# Generated by FakeRAM 2.0
VERSION 5.7 ;
BUSBITCHARS "[]" ;
PROPERTYDEFINITIONS
  MACRO width INTEGER ;
  MACRO depth INTEGER ;
  MACRO banks INTEGER ;
END PROPERTYDEFINITIONS
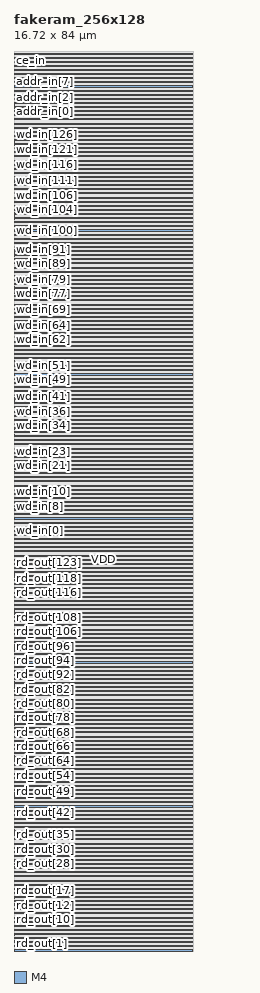
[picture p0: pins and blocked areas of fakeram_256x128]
MACRO fakeram_256x128
  PROPERTY width 128 ;
  PROPERTY depth 256 ;
  PROPERTY banks 1 ;
  FOREIGN fakeram_256x128 0 0 ;
  SYMMETRY X Y R90 ;
  SIZE 16.720 BY 84.000 ;
  CLASS BLOCK ;
  PIN rd_out[0]
    DIRECTION OUTPUT ;
    USE SIGNAL ;
    SHAPE ABUTMENT ;
    PORT
      LAYER M4 ;
      RECT 0.000 0.048 0.024 0.072 ;
    END
  END rd_out[0]
  PIN rd_out[1]
    DIRECTION OUTPUT ;
    USE SIGNAL ;
    SHAPE ABUTMENT ;
    PORT
      LAYER M4 ;
      RECT 0.000 0.336 0.024 0.360 ;
    END
  END rd_out[1]
  PIN rd_out[2]
    DIRECTION OUTPUT ;
    USE SIGNAL ;
    SHAPE ABUTMENT ;
    PORT
      LAYER M4 ;
      RECT 0.000 0.624 0.024 0.648 ;
    END
  END rd_out[2]
  PIN rd_out[3]
    DIRECTION OUTPUT ;
    USE SIGNAL ;
    SHAPE ABUTMENT ;
    PORT
      LAYER M4 ;
      RECT 0.000 0.912 0.024 0.936 ;
    END
  END rd_out[3]
  PIN rd_out[4]
    DIRECTION OUTPUT ;
    USE SIGNAL ;
    SHAPE ABUTMENT ;
    PORT
      LAYER M4 ;
      RECT 0.000 1.200 0.024 1.224 ;
    END
  END rd_out[4]
  PIN rd_out[5]
    DIRECTION OUTPUT ;
    USE SIGNAL ;
    SHAPE ABUTMENT ;
    PORT
      LAYER M4 ;
      RECT 0.000 1.488 0.024 1.512 ;
    END
  END rd_out[5]
  PIN rd_out[6]
    DIRECTION OUTPUT ;
    USE SIGNAL ;
    SHAPE ABUTMENT ;
    PORT
      LAYER M4 ;
      RECT 0.000 1.776 0.024 1.800 ;
    END
  END rd_out[6]
  PIN rd_out[7]
    DIRECTION OUTPUT ;
    USE SIGNAL ;
    SHAPE ABUTMENT ;
    PORT
      LAYER M4 ;
      RECT 0.000 2.064 0.024 2.088 ;
    END
  END rd_out[7]
  PIN rd_out[8]
    DIRECTION OUTPUT ;
    USE SIGNAL ;
    SHAPE ABUTMENT ;
    PORT
      LAYER M4 ;
      RECT 0.000 2.352 0.024 2.376 ;
    END
  END rd_out[8]
  PIN rd_out[9]
    DIRECTION OUTPUT ;
    USE SIGNAL ;
    SHAPE ABUTMENT ;
    PORT
      LAYER M4 ;
      RECT 0.000 2.640 0.024 2.664 ;
    END
  END rd_out[9]
  PIN rd_out[10]
    DIRECTION OUTPUT ;
    USE SIGNAL ;
    SHAPE ABUTMENT ;
    PORT
      LAYER M4 ;
      RECT 0.000 2.928 0.024 2.952 ;
    END
  END rd_out[10]
  PIN rd_out[11]
    DIRECTION OUTPUT ;
    USE SIGNAL ;
    SHAPE ABUTMENT ;
    PORT
      LAYER M4 ;
      RECT 0.000 3.216 0.024 3.240 ;
    END
  END rd_out[11]
  PIN rd_out[12]
    DIRECTION OUTPUT ;
    USE SIGNAL ;
    SHAPE ABUTMENT ;
    PORT
      LAYER M4 ;
      RECT 0.000 3.504 0.024 3.528 ;
    END
  END rd_out[12]
  PIN rd_out[13]
    DIRECTION OUTPUT ;
    USE SIGNAL ;
    SHAPE ABUTMENT ;
    PORT
      LAYER M4 ;
      RECT 0.000 3.792 0.024 3.816 ;
    END
  END rd_out[13]
  PIN rd_out[14]
    DIRECTION OUTPUT ;
    USE SIGNAL ;
    SHAPE ABUTMENT ;
    PORT
      LAYER M4 ;
      RECT 0.000 4.080 0.024 4.104 ;
    END
  END rd_out[14]
  PIN rd_out[15]
    DIRECTION OUTPUT ;
    USE SIGNAL ;
    SHAPE ABUTMENT ;
    PORT
      LAYER M4 ;
      RECT 0.000 4.368 0.024 4.392 ;
    END
  END rd_out[15]
  PIN rd_out[16]
    DIRECTION OUTPUT ;
    USE SIGNAL ;
    SHAPE ABUTMENT ;
    PORT
      LAYER M4 ;
      RECT 0.000 4.656 0.024 4.680 ;
    END
  END rd_out[16]
  PIN rd_out[17]
    DIRECTION OUTPUT ;
    USE SIGNAL ;
    SHAPE ABUTMENT ;
    PORT
      LAYER M4 ;
      RECT 0.000 4.944 0.024 4.968 ;
    END
  END rd_out[17]
  PIN rd_out[18]
    DIRECTION OUTPUT ;
    USE SIGNAL ;
    SHAPE ABUTMENT ;
    PORT
      LAYER M4 ;
      RECT 0.000 5.232 0.024 5.256 ;
    END
  END rd_out[18]
  PIN rd_out[19]
    DIRECTION OUTPUT ;
    USE SIGNAL ;
    SHAPE ABUTMENT ;
    PORT
      LAYER M4 ;
      RECT 0.000 5.520 0.024 5.544 ;
    END
  END rd_out[19]
  PIN rd_out[20]
    DIRECTION OUTPUT ;
    USE SIGNAL ;
    SHAPE ABUTMENT ;
    PORT
      LAYER M4 ;
      RECT 0.000 5.808 0.024 5.832 ;
    END
  END rd_out[20]
  PIN rd_out[21]
    DIRECTION OUTPUT ;
    USE SIGNAL ;
    SHAPE ABUTMENT ;
    PORT
      LAYER M4 ;
      RECT 0.000 6.096 0.024 6.120 ;
    END
  END rd_out[21]
  PIN rd_out[22]
    DIRECTION OUTPUT ;
    USE SIGNAL ;
    SHAPE ABUTMENT ;
    PORT
      LAYER M4 ;
      RECT 0.000 6.384 0.024 6.408 ;
    END
  END rd_out[22]
  PIN rd_out[23]
    DIRECTION OUTPUT ;
    USE SIGNAL ;
    SHAPE ABUTMENT ;
    PORT
      LAYER M4 ;
      RECT 0.000 6.672 0.024 6.696 ;
    END
  END rd_out[23]
  PIN rd_out[24]
    DIRECTION OUTPUT ;
    USE SIGNAL ;
    SHAPE ABUTMENT ;
    PORT
      LAYER M4 ;
      RECT 0.000 6.960 0.024 6.984 ;
    END
  END rd_out[24]
  PIN rd_out[25]
    DIRECTION OUTPUT ;
    USE SIGNAL ;
    SHAPE ABUTMENT ;
    PORT
      LAYER M4 ;
      RECT 0.000 7.248 0.024 7.272 ;
    END
  END rd_out[25]
  PIN rd_out[26]
    DIRECTION OUTPUT ;
    USE SIGNAL ;
    SHAPE ABUTMENT ;
    PORT
      LAYER M4 ;
      RECT 0.000 7.536 0.024 7.560 ;
    END
  END rd_out[26]
  PIN rd_out[27]
    DIRECTION OUTPUT ;
    USE SIGNAL ;
    SHAPE ABUTMENT ;
    PORT
      LAYER M4 ;
      RECT 0.000 7.824 0.024 7.848 ;
    END
  END rd_out[27]
  PIN rd_out[28]
    DIRECTION OUTPUT ;
    USE SIGNAL ;
    SHAPE ABUTMENT ;
    PORT
      LAYER M4 ;
      RECT 0.000 8.112 0.024 8.136 ;
    END
  END rd_out[28]
  PIN rd_out[29]
    DIRECTION OUTPUT ;
    USE SIGNAL ;
    SHAPE ABUTMENT ;
    PORT
      LAYER M4 ;
      RECT 0.000 8.400 0.024 8.424 ;
    END
  END rd_out[29]
  PIN rd_out[30]
    DIRECTION OUTPUT ;
    USE SIGNAL ;
    SHAPE ABUTMENT ;
    PORT
      LAYER M4 ;
      RECT 0.000 8.688 0.024 8.712 ;
    END
  END rd_out[30]
  PIN rd_out[31]
    DIRECTION OUTPUT ;
    USE SIGNAL ;
    SHAPE ABUTMENT ;
    PORT
      LAYER M4 ;
      RECT 0.000 8.976 0.024 9.000 ;
    END
  END rd_out[31]
  PIN rd_out[32]
    DIRECTION OUTPUT ;
    USE SIGNAL ;
    SHAPE ABUTMENT ;
    PORT
      LAYER M4 ;
      RECT 0.000 9.264 0.024 9.288 ;
    END
  END rd_out[32]
  PIN rd_out[33]
    DIRECTION OUTPUT ;
    USE SIGNAL ;
    SHAPE ABUTMENT ;
    PORT
      LAYER M4 ;
      RECT 0.000 9.552 0.024 9.576 ;
    END
  END rd_out[33]
  PIN rd_out[34]
    DIRECTION OUTPUT ;
    USE SIGNAL ;
    SHAPE ABUTMENT ;
    PORT
      LAYER M4 ;
      RECT 0.000 9.840 0.024 9.864 ;
    END
  END rd_out[34]
  PIN rd_out[35]
    DIRECTION OUTPUT ;
    USE SIGNAL ;
    SHAPE ABUTMENT ;
    PORT
      LAYER M4 ;
      RECT 0.000 10.128 0.024 10.152 ;
    END
  END rd_out[35]
  PIN rd_out[36]
    DIRECTION OUTPUT ;
    USE SIGNAL ;
    SHAPE ABUTMENT ;
    PORT
      LAYER M4 ;
      RECT 0.000 10.416 0.024 10.440 ;
    END
  END rd_out[36]
  PIN rd_out[37]
    DIRECTION OUTPUT ;
    USE SIGNAL ;
    SHAPE ABUTMENT ;
    PORT
      LAYER M4 ;
      RECT 0.000 10.704 0.024 10.728 ;
    END
  END rd_out[37]
  PIN rd_out[38]
    DIRECTION OUTPUT ;
    USE SIGNAL ;
    SHAPE ABUTMENT ;
    PORT
      LAYER M4 ;
      RECT 0.000 10.992 0.024 11.016 ;
    END
  END rd_out[38]
  PIN rd_out[39]
    DIRECTION OUTPUT ;
    USE SIGNAL ;
    SHAPE ABUTMENT ;
    PORT
      LAYER M4 ;
      RECT 0.000 11.280 0.024 11.304 ;
    END
  END rd_out[39]
  PIN rd_out[40]
    DIRECTION OUTPUT ;
    USE SIGNAL ;
    SHAPE ABUTMENT ;
    PORT
      LAYER M4 ;
      RECT 0.000 11.568 0.024 11.592 ;
    END
  END rd_out[40]
  PIN rd_out[41]
    DIRECTION OUTPUT ;
    USE SIGNAL ;
    SHAPE ABUTMENT ;
    PORT
      LAYER M4 ;
      RECT 0.000 11.856 0.024 11.880 ;
    END
  END rd_out[41]
  PIN rd_out[42]
    DIRECTION OUTPUT ;
    USE SIGNAL ;
    SHAPE ABUTMENT ;
    PORT
      LAYER M4 ;
      RECT 0.000 12.144 0.024 12.168 ;
    END
  END rd_out[42]
  PIN rd_out[43]
    DIRECTION OUTPUT ;
    USE SIGNAL ;
    SHAPE ABUTMENT ;
    PORT
      LAYER M4 ;
      RECT 0.000 12.432 0.024 12.456 ;
    END
  END rd_out[43]
  PIN rd_out[44]
    DIRECTION OUTPUT ;
    USE SIGNAL ;
    SHAPE ABUTMENT ;
    PORT
      LAYER M4 ;
      RECT 0.000 12.720 0.024 12.744 ;
    END
  END rd_out[44]
  PIN rd_out[45]
    DIRECTION OUTPUT ;
    USE SIGNAL ;
    SHAPE ABUTMENT ;
    PORT
      LAYER M4 ;
      RECT 0.000 13.008 0.024 13.032 ;
    END
  END rd_out[45]
  PIN rd_out[46]
    DIRECTION OUTPUT ;
    USE SIGNAL ;
    SHAPE ABUTMENT ;
    PORT
      LAYER M4 ;
      RECT 0.000 13.296 0.024 13.320 ;
    END
  END rd_out[46]
  PIN rd_out[47]
    DIRECTION OUTPUT ;
    USE SIGNAL ;
    SHAPE ABUTMENT ;
    PORT
      LAYER M4 ;
      RECT 0.000 13.584 0.024 13.608 ;
    END
  END rd_out[47]
  PIN rd_out[48]
    DIRECTION OUTPUT ;
    USE SIGNAL ;
    SHAPE ABUTMENT ;
    PORT
      LAYER M4 ;
      RECT 0.000 13.872 0.024 13.896 ;
    END
  END rd_out[48]
  PIN rd_out[49]
    DIRECTION OUTPUT ;
    USE SIGNAL ;
    SHAPE ABUTMENT ;
    PORT
      LAYER M4 ;
      RECT 0.000 14.160 0.024 14.184 ;
    END
  END rd_out[49]
  PIN rd_out[50]
    DIRECTION OUTPUT ;
    USE SIGNAL ;
    SHAPE ABUTMENT ;
    PORT
      LAYER M4 ;
      RECT 0.000 14.448 0.024 14.472 ;
    END
  END rd_out[50]
  PIN rd_out[51]
    DIRECTION OUTPUT ;
    USE SIGNAL ;
    SHAPE ABUTMENT ;
    PORT
      LAYER M4 ;
      RECT 0.000 14.736 0.024 14.760 ;
    END
  END rd_out[51]
  PIN rd_out[52]
    DIRECTION OUTPUT ;
    USE SIGNAL ;
    SHAPE ABUTMENT ;
    PORT
      LAYER M4 ;
      RECT 0.000 15.024 0.024 15.048 ;
    END
  END rd_out[52]
  PIN rd_out[53]
    DIRECTION OUTPUT ;
    USE SIGNAL ;
    SHAPE ABUTMENT ;
    PORT
      LAYER M4 ;
      RECT 0.000 15.312 0.024 15.336 ;
    END
  END rd_out[53]
  PIN rd_out[54]
    DIRECTION OUTPUT ;
    USE SIGNAL ;
    SHAPE ABUTMENT ;
    PORT
      LAYER M4 ;
      RECT 0.000 15.600 0.024 15.624 ;
    END
  END rd_out[54]
  PIN rd_out[55]
    DIRECTION OUTPUT ;
    USE SIGNAL ;
    SHAPE ABUTMENT ;
    PORT
      LAYER M4 ;
      RECT 0.000 15.888 0.024 15.912 ;
    END
  END rd_out[55]
  PIN rd_out[56]
    DIRECTION OUTPUT ;
    USE SIGNAL ;
    SHAPE ABUTMENT ;
    PORT
      LAYER M4 ;
      RECT 0.000 16.176 0.024 16.200 ;
    END
  END rd_out[56]
  PIN rd_out[57]
    DIRECTION OUTPUT ;
    USE SIGNAL ;
    SHAPE ABUTMENT ;
    PORT
      LAYER M4 ;
      RECT 0.000 16.464 0.024 16.488 ;
    END
  END rd_out[57]
  PIN rd_out[58]
    DIRECTION OUTPUT ;
    USE SIGNAL ;
    SHAPE ABUTMENT ;
    PORT
      LAYER M4 ;
      RECT 0.000 16.752 0.024 16.776 ;
    END
  END rd_out[58]
  PIN rd_out[59]
    DIRECTION OUTPUT ;
    USE SIGNAL ;
    SHAPE ABUTMENT ;
    PORT
      LAYER M4 ;
      RECT 0.000 17.040 0.024 17.064 ;
    END
  END rd_out[59]
  PIN rd_out[60]
    DIRECTION OUTPUT ;
    USE SIGNAL ;
    SHAPE ABUTMENT ;
    PORT
      LAYER M4 ;
      RECT 0.000 17.328 0.024 17.352 ;
    END
  END rd_out[60]
  PIN rd_out[61]
    DIRECTION OUTPUT ;
    USE SIGNAL ;
    SHAPE ABUTMENT ;
    PORT
      LAYER M4 ;
      RECT 0.000 17.616 0.024 17.640 ;
    END
  END rd_out[61]
  PIN rd_out[62]
    DIRECTION OUTPUT ;
    USE SIGNAL ;
    SHAPE ABUTMENT ;
    PORT
      LAYER M4 ;
      RECT 0.000 17.904 0.024 17.928 ;
    END
  END rd_out[62]
  PIN rd_out[63]
    DIRECTION OUTPUT ;
    USE SIGNAL ;
    SHAPE ABUTMENT ;
    PORT
      LAYER M4 ;
      RECT 0.000 18.192 0.024 18.216 ;
    END
  END rd_out[63]
  PIN rd_out[64]
    DIRECTION OUTPUT ;
    USE SIGNAL ;
    SHAPE ABUTMENT ;
    PORT
      LAYER M4 ;
      RECT 0.000 18.480 0.024 18.504 ;
    END
  END rd_out[64]
  PIN rd_out[65]
    DIRECTION OUTPUT ;
    USE SIGNAL ;
    SHAPE ABUTMENT ;
    PORT
      LAYER M4 ;
      RECT 0.000 18.768 0.024 18.792 ;
    END
  END rd_out[65]
  PIN rd_out[66]
    DIRECTION OUTPUT ;
    USE SIGNAL ;
    SHAPE ABUTMENT ;
    PORT
      LAYER M4 ;
      RECT 0.000 19.056 0.024 19.080 ;
    END
  END rd_out[66]
  PIN rd_out[67]
    DIRECTION OUTPUT ;
    USE SIGNAL ;
    SHAPE ABUTMENT ;
    PORT
      LAYER M4 ;
      RECT 0.000 19.344 0.024 19.368 ;
    END
  END rd_out[67]
  PIN rd_out[68]
    DIRECTION OUTPUT ;
    USE SIGNAL ;
    SHAPE ABUTMENT ;
    PORT
      LAYER M4 ;
      RECT 0.000 19.632 0.024 19.656 ;
    END
  END rd_out[68]
  PIN rd_out[69]
    DIRECTION OUTPUT ;
    USE SIGNAL ;
    SHAPE ABUTMENT ;
    PORT
      LAYER M4 ;
      RECT 0.000 19.920 0.024 19.944 ;
    END
  END rd_out[69]
  PIN rd_out[70]
    DIRECTION OUTPUT ;
    USE SIGNAL ;
    SHAPE ABUTMENT ;
    PORT
      LAYER M4 ;
      RECT 0.000 20.208 0.024 20.232 ;
    END
  END rd_out[70]
  PIN rd_out[71]
    DIRECTION OUTPUT ;
    USE SIGNAL ;
    SHAPE ABUTMENT ;
    PORT
      LAYER M4 ;
      RECT 0.000 20.496 0.024 20.520 ;
    END
  END rd_out[71]
  PIN rd_out[72]
    DIRECTION OUTPUT ;
    USE SIGNAL ;
    SHAPE ABUTMENT ;
    PORT
      LAYER M4 ;
      RECT 0.000 20.784 0.024 20.808 ;
    END
  END rd_out[72]
  PIN rd_out[73]
    DIRECTION OUTPUT ;
    USE SIGNAL ;
    SHAPE ABUTMENT ;
    PORT
      LAYER M4 ;
      RECT 0.000 21.072 0.024 21.096 ;
    END
  END rd_out[73]
  PIN rd_out[74]
    DIRECTION OUTPUT ;
    USE SIGNAL ;
    SHAPE ABUTMENT ;
    PORT
      LAYER M4 ;
      RECT 0.000 21.360 0.024 21.384 ;
    END
  END rd_out[74]
  PIN rd_out[75]
    DIRECTION OUTPUT ;
    USE SIGNAL ;
    SHAPE ABUTMENT ;
    PORT
      LAYER M4 ;
      RECT 0.000 21.648 0.024 21.672 ;
    END
  END rd_out[75]
  PIN rd_out[76]
    DIRECTION OUTPUT ;
    USE SIGNAL ;
    SHAPE ABUTMENT ;
    PORT
      LAYER M4 ;
      RECT 0.000 21.936 0.024 21.960 ;
    END
  END rd_out[76]
  PIN rd_out[77]
    DIRECTION OUTPUT ;
    USE SIGNAL ;
    SHAPE ABUTMENT ;
    PORT
      LAYER M4 ;
      RECT 0.000 22.224 0.024 22.248 ;
    END
  END rd_out[77]
  PIN rd_out[78]
    DIRECTION OUTPUT ;
    USE SIGNAL ;
    SHAPE ABUTMENT ;
    PORT
      LAYER M4 ;
      RECT 0.000 22.512 0.024 22.536 ;
    END
  END rd_out[78]
  PIN rd_out[79]
    DIRECTION OUTPUT ;
    USE SIGNAL ;
    SHAPE ABUTMENT ;
    PORT
      LAYER M4 ;
      RECT 0.000 22.800 0.024 22.824 ;
    END
  END rd_out[79]
  PIN rd_out[80]
    DIRECTION OUTPUT ;
    USE SIGNAL ;
    SHAPE ABUTMENT ;
    PORT
      LAYER M4 ;
      RECT 0.000 23.088 0.024 23.112 ;
    END
  END rd_out[80]
  PIN rd_out[81]
    DIRECTION OUTPUT ;
    USE SIGNAL ;
    SHAPE ABUTMENT ;
    PORT
      LAYER M4 ;
      RECT 0.000 23.376 0.024 23.400 ;
    END
  END rd_out[81]
  PIN rd_out[82]
    DIRECTION OUTPUT ;
    USE SIGNAL ;
    SHAPE ABUTMENT ;
    PORT
      LAYER M4 ;
      RECT 0.000 23.664 0.024 23.688 ;
    END
  END rd_out[82]
  PIN rd_out[83]
    DIRECTION OUTPUT ;
    USE SIGNAL ;
    SHAPE ABUTMENT ;
    PORT
      LAYER M4 ;
      RECT 0.000 23.952 0.024 23.976 ;
    END
  END rd_out[83]
  PIN rd_out[84]
    DIRECTION OUTPUT ;
    USE SIGNAL ;
    SHAPE ABUTMENT ;
    PORT
      LAYER M4 ;
      RECT 0.000 24.240 0.024 24.264 ;
    END
  END rd_out[84]
  PIN rd_out[85]
    DIRECTION OUTPUT ;
    USE SIGNAL ;
    SHAPE ABUTMENT ;
    PORT
      LAYER M4 ;
      RECT 0.000 24.528 0.024 24.552 ;
    END
  END rd_out[85]
  PIN rd_out[86]
    DIRECTION OUTPUT ;
    USE SIGNAL ;
    SHAPE ABUTMENT ;
    PORT
      LAYER M4 ;
      RECT 0.000 24.816 0.024 24.840 ;
    END
  END rd_out[86]
  PIN rd_out[87]
    DIRECTION OUTPUT ;
    USE SIGNAL ;
    SHAPE ABUTMENT ;
    PORT
      LAYER M4 ;
      RECT 0.000 25.104 0.024 25.128 ;
    END
  END rd_out[87]
  PIN rd_out[88]
    DIRECTION OUTPUT ;
    USE SIGNAL ;
    SHAPE ABUTMENT ;
    PORT
      LAYER M4 ;
      RECT 0.000 25.392 0.024 25.416 ;
    END
  END rd_out[88]
  PIN rd_out[89]
    DIRECTION OUTPUT ;
    USE SIGNAL ;
    SHAPE ABUTMENT ;
    PORT
      LAYER M4 ;
      RECT 0.000 25.680 0.024 25.704 ;
    END
  END rd_out[89]
  PIN rd_out[90]
    DIRECTION OUTPUT ;
    USE SIGNAL ;
    SHAPE ABUTMENT ;
    PORT
      LAYER M4 ;
      RECT 0.000 25.968 0.024 25.992 ;
    END
  END rd_out[90]
  PIN rd_out[91]
    DIRECTION OUTPUT ;
    USE SIGNAL ;
    SHAPE ABUTMENT ;
    PORT
      LAYER M4 ;
      RECT 0.000 26.256 0.024 26.280 ;
    END
  END rd_out[91]
  PIN rd_out[92]
    DIRECTION OUTPUT ;
    USE SIGNAL ;
    SHAPE ABUTMENT ;
    PORT
      LAYER M4 ;
      RECT 0.000 26.544 0.024 26.568 ;
    END
  END rd_out[92]
  PIN rd_out[93]
    DIRECTION OUTPUT ;
    USE SIGNAL ;
    SHAPE ABUTMENT ;
    PORT
      LAYER M4 ;
      RECT 0.000 26.832 0.024 26.856 ;
    END
  END rd_out[93]
  PIN rd_out[94]
    DIRECTION OUTPUT ;
    USE SIGNAL ;
    SHAPE ABUTMENT ;
    PORT
      LAYER M4 ;
      RECT 0.000 27.120 0.024 27.144 ;
    END
  END rd_out[94]
  PIN rd_out[95]
    DIRECTION OUTPUT ;
    USE SIGNAL ;
    SHAPE ABUTMENT ;
    PORT
      LAYER M4 ;
      RECT 0.000 27.408 0.024 27.432 ;
    END
  END rd_out[95]
  PIN rd_out[96]
    DIRECTION OUTPUT ;
    USE SIGNAL ;
    SHAPE ABUTMENT ;
    PORT
      LAYER M4 ;
      RECT 0.000 27.696 0.024 27.720 ;
    END
  END rd_out[96]
  PIN rd_out[97]
    DIRECTION OUTPUT ;
    USE SIGNAL ;
    SHAPE ABUTMENT ;
    PORT
      LAYER M4 ;
      RECT 0.000 27.984 0.024 28.008 ;
    END
  END rd_out[97]
  PIN rd_out[98]
    DIRECTION OUTPUT ;
    USE SIGNAL ;
    SHAPE ABUTMENT ;
    PORT
      LAYER M4 ;
      RECT 0.000 28.272 0.024 28.296 ;
    END
  END rd_out[98]
  PIN rd_out[99]
    DIRECTION OUTPUT ;
    USE SIGNAL ;
    SHAPE ABUTMENT ;
    PORT
      LAYER M4 ;
      RECT 0.000 28.560 0.024 28.584 ;
    END
  END rd_out[99]
  PIN rd_out[100]
    DIRECTION OUTPUT ;
    USE SIGNAL ;
    SHAPE ABUTMENT ;
    PORT
      LAYER M4 ;
      RECT 0.000 28.848 0.024 28.872 ;
    END
  END rd_out[100]
  PIN rd_out[101]
    DIRECTION OUTPUT ;
    USE SIGNAL ;
    SHAPE ABUTMENT ;
    PORT
      LAYER M4 ;
      RECT 0.000 29.136 0.024 29.160 ;
    END
  END rd_out[101]
  PIN rd_out[102]
    DIRECTION OUTPUT ;
    USE SIGNAL ;
    SHAPE ABUTMENT ;
    PORT
      LAYER M4 ;
      RECT 0.000 29.424 0.024 29.448 ;
    END
  END rd_out[102]
  PIN rd_out[103]
    DIRECTION OUTPUT ;
    USE SIGNAL ;
    SHAPE ABUTMENT ;
    PORT
      LAYER M4 ;
      RECT 0.000 29.712 0.024 29.736 ;
    END
  END rd_out[103]
  PIN rd_out[104]
    DIRECTION OUTPUT ;
    USE SIGNAL ;
    SHAPE ABUTMENT ;
    PORT
      LAYER M4 ;
      RECT 0.000 30.000 0.024 30.024 ;
    END
  END rd_out[104]
  PIN rd_out[105]
    DIRECTION OUTPUT ;
    USE SIGNAL ;
    SHAPE ABUTMENT ;
    PORT
      LAYER M4 ;
      RECT 0.000 30.288 0.024 30.312 ;
    END
  END rd_out[105]
  PIN rd_out[106]
    DIRECTION OUTPUT ;
    USE SIGNAL ;
    SHAPE ABUTMENT ;
    PORT
      LAYER M4 ;
      RECT 0.000 30.576 0.024 30.600 ;
    END
  END rd_out[106]
  PIN rd_out[107]
    DIRECTION OUTPUT ;
    USE SIGNAL ;
    SHAPE ABUTMENT ;
    PORT
      LAYER M4 ;
      RECT 0.000 30.864 0.024 30.888 ;
    END
  END rd_out[107]
  PIN rd_out[108]
    DIRECTION OUTPUT ;
    USE SIGNAL ;
    SHAPE ABUTMENT ;
    PORT
      LAYER M4 ;
      RECT 0.000 31.152 0.024 31.176 ;
    END
  END rd_out[108]
  PIN rd_out[109]
    DIRECTION OUTPUT ;
    USE SIGNAL ;
    SHAPE ABUTMENT ;
    PORT
      LAYER M4 ;
      RECT 0.000 31.440 0.024 31.464 ;
    END
  END rd_out[109]
  PIN rd_out[110]
    DIRECTION OUTPUT ;
    USE SIGNAL ;
    SHAPE ABUTMENT ;
    PORT
      LAYER M4 ;
      RECT 0.000 31.728 0.024 31.752 ;
    END
  END rd_out[110]
  PIN rd_out[111]
    DIRECTION OUTPUT ;
    USE SIGNAL ;
    SHAPE ABUTMENT ;
    PORT
      LAYER M4 ;
      RECT 0.000 32.016 0.024 32.040 ;
    END
  END rd_out[111]
  PIN rd_out[112]
    DIRECTION OUTPUT ;
    USE SIGNAL ;
    SHAPE ABUTMENT ;
    PORT
      LAYER M4 ;
      RECT 0.000 32.304 0.024 32.328 ;
    END
  END rd_out[112]
  PIN rd_out[113]
    DIRECTION OUTPUT ;
    USE SIGNAL ;
    SHAPE ABUTMENT ;
    PORT
      LAYER M4 ;
      RECT 0.000 32.592 0.024 32.616 ;
    END
  END rd_out[113]
  PIN rd_out[114]
    DIRECTION OUTPUT ;
    USE SIGNAL ;
    SHAPE ABUTMENT ;
    PORT
      LAYER M4 ;
      RECT 0.000 32.880 0.024 32.904 ;
    END
  END rd_out[114]
  PIN rd_out[115]
    DIRECTION OUTPUT ;
    USE SIGNAL ;
    SHAPE ABUTMENT ;
    PORT
      LAYER M4 ;
      RECT 0.000 33.168 0.024 33.192 ;
    END
  END rd_out[115]
  PIN rd_out[116]
    DIRECTION OUTPUT ;
    USE SIGNAL ;
    SHAPE ABUTMENT ;
    PORT
      LAYER M4 ;
      RECT 0.000 33.456 0.024 33.480 ;
    END
  END rd_out[116]
  PIN rd_out[117]
    DIRECTION OUTPUT ;
    USE SIGNAL ;
    SHAPE ABUTMENT ;
    PORT
      LAYER M4 ;
      RECT 0.000 33.744 0.024 33.768 ;
    END
  END rd_out[117]
  PIN rd_out[118]
    DIRECTION OUTPUT ;
    USE SIGNAL ;
    SHAPE ABUTMENT ;
    PORT
      LAYER M4 ;
      RECT 0.000 34.032 0.024 34.056 ;
    END
  END rd_out[118]
  PIN rd_out[119]
    DIRECTION OUTPUT ;
    USE SIGNAL ;
    SHAPE ABUTMENT ;
    PORT
      LAYER M4 ;
      RECT 0.000 34.320 0.024 34.344 ;
    END
  END rd_out[119]
  PIN rd_out[120]
    DIRECTION OUTPUT ;
    USE SIGNAL ;
    SHAPE ABUTMENT ;
    PORT
      LAYER M4 ;
      RECT 0.000 34.608 0.024 34.632 ;
    END
  END rd_out[120]
  PIN rd_out[121]
    DIRECTION OUTPUT ;
    USE SIGNAL ;
    SHAPE ABUTMENT ;
    PORT
      LAYER M4 ;
      RECT 0.000 34.896 0.024 34.920 ;
    END
  END rd_out[121]
  PIN rd_out[122]
    DIRECTION OUTPUT ;
    USE SIGNAL ;
    SHAPE ABUTMENT ;
    PORT
      LAYER M4 ;
      RECT 0.000 35.184 0.024 35.208 ;
    END
  END rd_out[122]
  PIN rd_out[123]
    DIRECTION OUTPUT ;
    USE SIGNAL ;
    SHAPE ABUTMENT ;
    PORT
      LAYER M4 ;
      RECT 0.000 35.472 0.024 35.496 ;
    END
  END rd_out[123]
  PIN rd_out[124]
    DIRECTION OUTPUT ;
    USE SIGNAL ;
    SHAPE ABUTMENT ;
    PORT
      LAYER M4 ;
      RECT 0.000 35.760 0.024 35.784 ;
    END
  END rd_out[124]
  PIN rd_out[125]
    DIRECTION OUTPUT ;
    USE SIGNAL ;
    SHAPE ABUTMENT ;
    PORT
      LAYER M4 ;
      RECT 0.000 36.048 0.024 36.072 ;
    END
  END rd_out[125]
  PIN rd_out[126]
    DIRECTION OUTPUT ;
    USE SIGNAL ;
    SHAPE ABUTMENT ;
    PORT
      LAYER M4 ;
      RECT 0.000 36.336 0.024 36.360 ;
    END
  END rd_out[126]
  PIN rd_out[127]
    DIRECTION OUTPUT ;
    USE SIGNAL ;
    SHAPE ABUTMENT ;
    PORT
      LAYER M4 ;
      RECT 0.000 36.624 0.024 36.648 ;
    END
  END rd_out[127]
  PIN wd_in[0]
    DIRECTION INPUT ;
    USE SIGNAL ;
    SHAPE ABUTMENT ;
    PORT
      LAYER M4 ;
      RECT 0.000 39.216 0.024 39.240 ;
    END
  END wd_in[0]
  PIN wd_in[1]
    DIRECTION INPUT ;
    USE SIGNAL ;
    SHAPE ABUTMENT ;
    PORT
      LAYER M4 ;
      RECT 0.000 39.504 0.024 39.528 ;
    END
  END wd_in[1]
  PIN wd_in[2]
    DIRECTION INPUT ;
    USE SIGNAL ;
    SHAPE ABUTMENT ;
    PORT
      LAYER M4 ;
      RECT 0.000 39.792 0.024 39.816 ;
    END
  END wd_in[2]
  PIN wd_in[3]
    DIRECTION INPUT ;
    USE SIGNAL ;
    SHAPE ABUTMENT ;
    PORT
      LAYER M4 ;
      RECT 0.000 40.080 0.024 40.104 ;
    END
  END wd_in[3]
  PIN wd_in[4]
    DIRECTION INPUT ;
    USE SIGNAL ;
    SHAPE ABUTMENT ;
    PORT
      LAYER M4 ;
      RECT 0.000 40.368 0.024 40.392 ;
    END
  END wd_in[4]
  PIN wd_in[5]
    DIRECTION INPUT ;
    USE SIGNAL ;
    SHAPE ABUTMENT ;
    PORT
      LAYER M4 ;
      RECT 0.000 40.656 0.024 40.680 ;
    END
  END wd_in[5]
  PIN wd_in[6]
    DIRECTION INPUT ;
    USE SIGNAL ;
    SHAPE ABUTMENT ;
    PORT
      LAYER M4 ;
      RECT 0.000 40.944 0.024 40.968 ;
    END
  END wd_in[6]
  PIN wd_in[7]
    DIRECTION INPUT ;
    USE SIGNAL ;
    SHAPE ABUTMENT ;
    PORT
      LAYER M4 ;
      RECT 0.000 41.232 0.024 41.256 ;
    END
  END wd_in[7]
  PIN wd_in[8]
    DIRECTION INPUT ;
    USE SIGNAL ;
    SHAPE ABUTMENT ;
    PORT
      LAYER M4 ;
      RECT 0.000 41.520 0.024 41.544 ;
    END
  END wd_in[8]
  PIN wd_in[9]
    DIRECTION INPUT ;
    USE SIGNAL ;
    SHAPE ABUTMENT ;
    PORT
      LAYER M4 ;
      RECT 0.000 41.808 0.024 41.832 ;
    END
  END wd_in[9]
  PIN wd_in[10]
    DIRECTION INPUT ;
    USE SIGNAL ;
    SHAPE ABUTMENT ;
    PORT
      LAYER M4 ;
      RECT 0.000 42.096 0.024 42.120 ;
    END
  END wd_in[10]
  PIN wd_in[11]
    DIRECTION INPUT ;
    USE SIGNAL ;
    SHAPE ABUTMENT ;
    PORT
      LAYER M4 ;
      RECT 0.000 42.384 0.024 42.408 ;
    END
  END wd_in[11]
  PIN wd_in[12]
    DIRECTION INPUT ;
    USE SIGNAL ;
    SHAPE ABUTMENT ;
    PORT
      LAYER M4 ;
      RECT 0.000 42.672 0.024 42.696 ;
    END
  END wd_in[12]
  PIN wd_in[13]
    DIRECTION INPUT ;
    USE SIGNAL ;
    SHAPE ABUTMENT ;
    PORT
      LAYER M4 ;
      RECT 0.000 42.960 0.024 42.984 ;
    END
  END wd_in[13]
  PIN wd_in[14]
    DIRECTION INPUT ;
    USE SIGNAL ;
    SHAPE ABUTMENT ;
    PORT
      LAYER M4 ;
      RECT 0.000 43.248 0.024 43.272 ;
    END
  END wd_in[14]
  PIN wd_in[15]
    DIRECTION INPUT ;
    USE SIGNAL ;
    SHAPE ABUTMENT ;
    PORT
      LAYER M4 ;
      RECT 0.000 43.536 0.024 43.560 ;
    END
  END wd_in[15]
  PIN wd_in[16]
    DIRECTION INPUT ;
    USE SIGNAL ;
    SHAPE ABUTMENT ;
    PORT
      LAYER M4 ;
      RECT 0.000 43.824 0.024 43.848 ;
    END
  END wd_in[16]
  PIN wd_in[17]
    DIRECTION INPUT ;
    USE SIGNAL ;
    SHAPE ABUTMENT ;
    PORT
      LAYER M4 ;
      RECT 0.000 44.112 0.024 44.136 ;
    END
  END wd_in[17]
  PIN wd_in[18]
    DIRECTION INPUT ;
    USE SIGNAL ;
    SHAPE ABUTMENT ;
    PORT
      LAYER M4 ;
      RECT 0.000 44.400 0.024 44.424 ;
    END
  END wd_in[18]
  PIN wd_in[19]
    DIRECTION INPUT ;
    USE SIGNAL ;
    SHAPE ABUTMENT ;
    PORT
      LAYER M4 ;
      RECT 0.000 44.688 0.024 44.712 ;
    END
  END wd_in[19]
  PIN wd_in[20]
    DIRECTION INPUT ;
    USE SIGNAL ;
    SHAPE ABUTMENT ;
    PORT
      LAYER M4 ;
      RECT 0.000 44.976 0.024 45.000 ;
    END
  END wd_in[20]
  PIN wd_in[21]
    DIRECTION INPUT ;
    USE SIGNAL ;
    SHAPE ABUTMENT ;
    PORT
      LAYER M4 ;
      RECT 0.000 45.264 0.024 45.288 ;
    END
  END wd_in[21]
  PIN wd_in[22]
    DIRECTION INPUT ;
    USE SIGNAL ;
    SHAPE ABUTMENT ;
    PORT
      LAYER M4 ;
      RECT 0.000 45.552 0.024 45.576 ;
    END
  END wd_in[22]
  PIN wd_in[23]
    DIRECTION INPUT ;
    USE SIGNAL ;
    SHAPE ABUTMENT ;
    PORT
      LAYER M4 ;
      RECT 0.000 45.840 0.024 45.864 ;
    END
  END wd_in[23]
  PIN wd_in[24]
    DIRECTION INPUT ;
    USE SIGNAL ;
    SHAPE ABUTMENT ;
    PORT
      LAYER M4 ;
      RECT 0.000 46.128 0.024 46.152 ;
    END
  END wd_in[24]
  PIN wd_in[25]
    DIRECTION INPUT ;
    USE SIGNAL ;
    SHAPE ABUTMENT ;
    PORT
      LAYER M4 ;
      RECT 0.000 46.416 0.024 46.440 ;
    END
  END wd_in[25]
  PIN wd_in[26]
    DIRECTION INPUT ;
    USE SIGNAL ;
    SHAPE ABUTMENT ;
    PORT
      LAYER M4 ;
      RECT 0.000 46.704 0.024 46.728 ;
    END
  END wd_in[26]
  PIN wd_in[27]
    DIRECTION INPUT ;
    USE SIGNAL ;
    SHAPE ABUTMENT ;
    PORT
      LAYER M4 ;
      RECT 0.000 46.992 0.024 47.016 ;
    END
  END wd_in[27]
  PIN wd_in[28]
    DIRECTION INPUT ;
    USE SIGNAL ;
    SHAPE ABUTMENT ;
    PORT
      LAYER M4 ;
      RECT 0.000 47.280 0.024 47.304 ;
    END
  END wd_in[28]
  PIN wd_in[29]
    DIRECTION INPUT ;
    USE SIGNAL ;
    SHAPE ABUTMENT ;
    PORT
      LAYER M4 ;
      RECT 0.000 47.568 0.024 47.592 ;
    END
  END wd_in[29]
  PIN wd_in[30]
    DIRECTION INPUT ;
    USE SIGNAL ;
    SHAPE ABUTMENT ;
    PORT
      LAYER M4 ;
      RECT 0.000 47.856 0.024 47.880 ;
    END
  END wd_in[30]
  PIN wd_in[31]
    DIRECTION INPUT ;
    USE SIGNAL ;
    SHAPE ABUTMENT ;
    PORT
      LAYER M4 ;
      RECT 0.000 48.144 0.024 48.168 ;
    END
  END wd_in[31]
  PIN wd_in[32]
    DIRECTION INPUT ;
    USE SIGNAL ;
    SHAPE ABUTMENT ;
    PORT
      LAYER M4 ;
      RECT 0.000 48.432 0.024 48.456 ;
    END
  END wd_in[32]
  PIN wd_in[33]
    DIRECTION INPUT ;
    USE SIGNAL ;
    SHAPE ABUTMENT ;
    PORT
      LAYER M4 ;
      RECT 0.000 48.720 0.024 48.744 ;
    END
  END wd_in[33]
  PIN wd_in[34]
    DIRECTION INPUT ;
    USE SIGNAL ;
    SHAPE ABUTMENT ;
    PORT
      LAYER M4 ;
      RECT 0.000 49.008 0.024 49.032 ;
    END
  END wd_in[34]
  PIN wd_in[35]
    DIRECTION INPUT ;
    USE SIGNAL ;
    SHAPE ABUTMENT ;
    PORT
      LAYER M4 ;
      RECT 0.000 49.296 0.024 49.320 ;
    END
  END wd_in[35]
  PIN wd_in[36]
    DIRECTION INPUT ;
    USE SIGNAL ;
    SHAPE ABUTMENT ;
    PORT
      LAYER M4 ;
      RECT 0.000 49.584 0.024 49.608 ;
    END
  END wd_in[36]
  PIN wd_in[37]
    DIRECTION INPUT ;
    USE SIGNAL ;
    SHAPE ABUTMENT ;
    PORT
      LAYER M4 ;
      RECT 0.000 49.872 0.024 49.896 ;
    END
  END wd_in[37]
  PIN wd_in[38]
    DIRECTION INPUT ;
    USE SIGNAL ;
    SHAPE ABUTMENT ;
    PORT
      LAYER M4 ;
      RECT 0.000 50.160 0.024 50.184 ;
    END
  END wd_in[38]
  PIN wd_in[39]
    DIRECTION INPUT ;
    USE SIGNAL ;
    SHAPE ABUTMENT ;
    PORT
      LAYER M4 ;
      RECT 0.000 50.448 0.024 50.472 ;
    END
  END wd_in[39]
  PIN wd_in[40]
    DIRECTION INPUT ;
    USE SIGNAL ;
    SHAPE ABUTMENT ;
    PORT
      LAYER M4 ;
      RECT 0.000 50.736 0.024 50.760 ;
    END
  END wd_in[40]
  PIN wd_in[41]
    DIRECTION INPUT ;
    USE SIGNAL ;
    SHAPE ABUTMENT ;
    PORT
      LAYER M4 ;
      RECT 0.000 51.024 0.024 51.048 ;
    END
  END wd_in[41]
  PIN wd_in[42]
    DIRECTION INPUT ;
    USE SIGNAL ;
    SHAPE ABUTMENT ;
    PORT
      LAYER M4 ;
      RECT 0.000 51.312 0.024 51.336 ;
    END
  END wd_in[42]
  PIN wd_in[43]
    DIRECTION INPUT ;
    USE SIGNAL ;
    SHAPE ABUTMENT ;
    PORT
      LAYER M4 ;
      RECT 0.000 51.600 0.024 51.624 ;
    END
  END wd_in[43]
  PIN wd_in[44]
    DIRECTION INPUT ;
    USE SIGNAL ;
    SHAPE ABUTMENT ;
    PORT
      LAYER M4 ;
      RECT 0.000 51.888 0.024 51.912 ;
    END
  END wd_in[44]
  PIN wd_in[45]
    DIRECTION INPUT ;
    USE SIGNAL ;
    SHAPE ABUTMENT ;
    PORT
      LAYER M4 ;
      RECT 0.000 52.176 0.024 52.200 ;
    END
  END wd_in[45]
  PIN wd_in[46]
    DIRECTION INPUT ;
    USE SIGNAL ;
    SHAPE ABUTMENT ;
    PORT
      LAYER M4 ;
      RECT 0.000 52.464 0.024 52.488 ;
    END
  END wd_in[46]
  PIN wd_in[47]
    DIRECTION INPUT ;
    USE SIGNAL ;
    SHAPE ABUTMENT ;
    PORT
      LAYER M4 ;
      RECT 0.000 52.752 0.024 52.776 ;
    END
  END wd_in[47]
  PIN wd_in[48]
    DIRECTION INPUT ;
    USE SIGNAL ;
    SHAPE ABUTMENT ;
    PORT
      LAYER M4 ;
      RECT 0.000 53.040 0.024 53.064 ;
    END
  END wd_in[48]
  PIN wd_in[49]
    DIRECTION INPUT ;
    USE SIGNAL ;
    SHAPE ABUTMENT ;
    PORT
      LAYER M4 ;
      RECT 0.000 53.328 0.024 53.352 ;
    END
  END wd_in[49]
  PIN wd_in[50]
    DIRECTION INPUT ;
    USE SIGNAL ;
    SHAPE ABUTMENT ;
    PORT
      LAYER M4 ;
      RECT 0.000 53.616 0.024 53.640 ;
    END
  END wd_in[50]
  PIN wd_in[51]
    DIRECTION INPUT ;
    USE SIGNAL ;
    SHAPE ABUTMENT ;
    PORT
      LAYER M4 ;
      RECT 0.000 53.904 0.024 53.928 ;
    END
  END wd_in[51]
  PIN wd_in[52]
    DIRECTION INPUT ;
    USE SIGNAL ;
    SHAPE ABUTMENT ;
    PORT
      LAYER M4 ;
      RECT 0.000 54.192 0.024 54.216 ;
    END
  END wd_in[52]
  PIN wd_in[53]
    DIRECTION INPUT ;
    USE SIGNAL ;
    SHAPE ABUTMENT ;
    PORT
      LAYER M4 ;
      RECT 0.000 54.480 0.024 54.504 ;
    END
  END wd_in[53]
  PIN wd_in[54]
    DIRECTION INPUT ;
    USE SIGNAL ;
    SHAPE ABUTMENT ;
    PORT
      LAYER M4 ;
      RECT 0.000 54.768 0.024 54.792 ;
    END
  END wd_in[54]
  PIN wd_in[55]
    DIRECTION INPUT ;
    USE SIGNAL ;
    SHAPE ABUTMENT ;
    PORT
      LAYER M4 ;
      RECT 0.000 55.056 0.024 55.080 ;
    END
  END wd_in[55]
  PIN wd_in[56]
    DIRECTION INPUT ;
    USE SIGNAL ;
    SHAPE ABUTMENT ;
    PORT
      LAYER M4 ;
      RECT 0.000 55.344 0.024 55.368 ;
    END
  END wd_in[56]
  PIN wd_in[57]
    DIRECTION INPUT ;
    USE SIGNAL ;
    SHAPE ABUTMENT ;
    PORT
      LAYER M4 ;
      RECT 0.000 55.632 0.024 55.656 ;
    END
  END wd_in[57]
  PIN wd_in[58]
    DIRECTION INPUT ;
    USE SIGNAL ;
    SHAPE ABUTMENT ;
    PORT
      LAYER M4 ;
      RECT 0.000 55.920 0.024 55.944 ;
    END
  END wd_in[58]
  PIN wd_in[59]
    DIRECTION INPUT ;
    USE SIGNAL ;
    SHAPE ABUTMENT ;
    PORT
      LAYER M4 ;
      RECT 0.000 56.208 0.024 56.232 ;
    END
  END wd_in[59]
  PIN wd_in[60]
    DIRECTION INPUT ;
    USE SIGNAL ;
    SHAPE ABUTMENT ;
    PORT
      LAYER M4 ;
      RECT 0.000 56.496 0.024 56.520 ;
    END
  END wd_in[60]
  PIN wd_in[61]
    DIRECTION INPUT ;
    USE SIGNAL ;
    SHAPE ABUTMENT ;
    PORT
      LAYER M4 ;
      RECT 0.000 56.784 0.024 56.808 ;
    END
  END wd_in[61]
  PIN wd_in[62]
    DIRECTION INPUT ;
    USE SIGNAL ;
    SHAPE ABUTMENT ;
    PORT
      LAYER M4 ;
      RECT 0.000 57.072 0.024 57.096 ;
    END
  END wd_in[62]
  PIN wd_in[63]
    DIRECTION INPUT ;
    USE SIGNAL ;
    SHAPE ABUTMENT ;
    PORT
      LAYER M4 ;
      RECT 0.000 57.360 0.024 57.384 ;
    END
  END wd_in[63]
  PIN wd_in[64]
    DIRECTION INPUT ;
    USE SIGNAL ;
    SHAPE ABUTMENT ;
    PORT
      LAYER M4 ;
      RECT 0.000 57.648 0.024 57.672 ;
    END
  END wd_in[64]
  PIN wd_in[65]
    DIRECTION INPUT ;
    USE SIGNAL ;
    SHAPE ABUTMENT ;
    PORT
      LAYER M4 ;
      RECT 0.000 57.936 0.024 57.960 ;
    END
  END wd_in[65]
  PIN wd_in[66]
    DIRECTION INPUT ;
    USE SIGNAL ;
    SHAPE ABUTMENT ;
    PORT
      LAYER M4 ;
      RECT 0.000 58.224 0.024 58.248 ;
    END
  END wd_in[66]
  PIN wd_in[67]
    DIRECTION INPUT ;
    USE SIGNAL ;
    SHAPE ABUTMENT ;
    PORT
      LAYER M4 ;
      RECT 0.000 58.512 0.024 58.536 ;
    END
  END wd_in[67]
  PIN wd_in[68]
    DIRECTION INPUT ;
    USE SIGNAL ;
    SHAPE ABUTMENT ;
    PORT
      LAYER M4 ;
      RECT 0.000 58.800 0.024 58.824 ;
    END
  END wd_in[68]
  PIN wd_in[69]
    DIRECTION INPUT ;
    USE SIGNAL ;
    SHAPE ABUTMENT ;
    PORT
      LAYER M4 ;
      RECT 0.000 59.088 0.024 59.112 ;
    END
  END wd_in[69]
  PIN wd_in[70]
    DIRECTION INPUT ;
    USE SIGNAL ;
    SHAPE ABUTMENT ;
    PORT
      LAYER M4 ;
      RECT 0.000 59.376 0.024 59.400 ;
    END
  END wd_in[70]
  PIN wd_in[71]
    DIRECTION INPUT ;
    USE SIGNAL ;
    SHAPE ABUTMENT ;
    PORT
      LAYER M4 ;
      RECT 0.000 59.664 0.024 59.688 ;
    END
  END wd_in[71]
  PIN wd_in[72]
    DIRECTION INPUT ;
    USE SIGNAL ;
    SHAPE ABUTMENT ;
    PORT
      LAYER M4 ;
      RECT 0.000 59.952 0.024 59.976 ;
    END
  END wd_in[72]
  PIN wd_in[73]
    DIRECTION INPUT ;
    USE SIGNAL ;
    SHAPE ABUTMENT ;
    PORT
      LAYER M4 ;
      RECT 0.000 60.240 0.024 60.264 ;
    END
  END wd_in[73]
  PIN wd_in[74]
    DIRECTION INPUT ;
    USE SIGNAL ;
    SHAPE ABUTMENT ;
    PORT
      LAYER M4 ;
      RECT 0.000 60.528 0.024 60.552 ;
    END
  END wd_in[74]
  PIN wd_in[75]
    DIRECTION INPUT ;
    USE SIGNAL ;
    SHAPE ABUTMENT ;
    PORT
      LAYER M4 ;
      RECT 0.000 60.816 0.024 60.840 ;
    END
  END wd_in[75]
  PIN wd_in[76]
    DIRECTION INPUT ;
    USE SIGNAL ;
    SHAPE ABUTMENT ;
    PORT
      LAYER M4 ;
      RECT 0.000 61.104 0.024 61.128 ;
    END
  END wd_in[76]
  PIN wd_in[77]
    DIRECTION INPUT ;
    USE SIGNAL ;
    SHAPE ABUTMENT ;
    PORT
      LAYER M4 ;
      RECT 0.000 61.392 0.024 61.416 ;
    END
  END wd_in[77]
  PIN wd_in[78]
    DIRECTION INPUT ;
    USE SIGNAL ;
    SHAPE ABUTMENT ;
    PORT
      LAYER M4 ;
      RECT 0.000 61.680 0.024 61.704 ;
    END
  END wd_in[78]
  PIN wd_in[79]
    DIRECTION INPUT ;
    USE SIGNAL ;
    SHAPE ABUTMENT ;
    PORT
      LAYER M4 ;
      RECT 0.000 61.968 0.024 61.992 ;
    END
  END wd_in[79]
  PIN wd_in[80]
    DIRECTION INPUT ;
    USE SIGNAL ;
    SHAPE ABUTMENT ;
    PORT
      LAYER M4 ;
      RECT 0.000 62.256 0.024 62.280 ;
    END
  END wd_in[80]
  PIN wd_in[81]
    DIRECTION INPUT ;
    USE SIGNAL ;
    SHAPE ABUTMENT ;
    PORT
      LAYER M4 ;
      RECT 0.000 62.544 0.024 62.568 ;
    END
  END wd_in[81]
  PIN wd_in[82]
    DIRECTION INPUT ;
    USE SIGNAL ;
    SHAPE ABUTMENT ;
    PORT
      LAYER M4 ;
      RECT 0.000 62.832 0.024 62.856 ;
    END
  END wd_in[82]
  PIN wd_in[83]
    DIRECTION INPUT ;
    USE SIGNAL ;
    SHAPE ABUTMENT ;
    PORT
      LAYER M4 ;
      RECT 0.000 63.120 0.024 63.144 ;
    END
  END wd_in[83]
  PIN wd_in[84]
    DIRECTION INPUT ;
    USE SIGNAL ;
    SHAPE ABUTMENT ;
    PORT
      LAYER M4 ;
      RECT 0.000 63.408 0.024 63.432 ;
    END
  END wd_in[84]
  PIN wd_in[85]
    DIRECTION INPUT ;
    USE SIGNAL ;
    SHAPE ABUTMENT ;
    PORT
      LAYER M4 ;
      RECT 0.000 63.696 0.024 63.720 ;
    END
  END wd_in[85]
  PIN wd_in[86]
    DIRECTION INPUT ;
    USE SIGNAL ;
    SHAPE ABUTMENT ;
    PORT
      LAYER M4 ;
      RECT 0.000 63.984 0.024 64.008 ;
    END
  END wd_in[86]
  PIN wd_in[87]
    DIRECTION INPUT ;
    USE SIGNAL ;
    SHAPE ABUTMENT ;
    PORT
      LAYER M4 ;
      RECT 0.000 64.272 0.024 64.296 ;
    END
  END wd_in[87]
  PIN wd_in[88]
    DIRECTION INPUT ;
    USE SIGNAL ;
    SHAPE ABUTMENT ;
    PORT
      LAYER M4 ;
      RECT 0.000 64.560 0.024 64.584 ;
    END
  END wd_in[88]
  PIN wd_in[89]
    DIRECTION INPUT ;
    USE SIGNAL ;
    SHAPE ABUTMENT ;
    PORT
      LAYER M4 ;
      RECT 0.000 64.848 0.024 64.872 ;
    END
  END wd_in[89]
  PIN wd_in[90]
    DIRECTION INPUT ;
    USE SIGNAL ;
    SHAPE ABUTMENT ;
    PORT
      LAYER M4 ;
      RECT 0.000 65.136 0.024 65.160 ;
    END
  END wd_in[90]
  PIN wd_in[91]
    DIRECTION INPUT ;
    USE SIGNAL ;
    SHAPE ABUTMENT ;
    PORT
      LAYER M4 ;
      RECT 0.000 65.424 0.024 65.448 ;
    END
  END wd_in[91]
  PIN wd_in[92]
    DIRECTION INPUT ;
    USE SIGNAL ;
    SHAPE ABUTMENT ;
    PORT
      LAYER M4 ;
      RECT 0.000 65.712 0.024 65.736 ;
    END
  END wd_in[92]
  PIN wd_in[93]
    DIRECTION INPUT ;
    USE SIGNAL ;
    SHAPE ABUTMENT ;
    PORT
      LAYER M4 ;
      RECT 0.000 66.000 0.024 66.024 ;
    END
  END wd_in[93]
  PIN wd_in[94]
    DIRECTION INPUT ;
    USE SIGNAL ;
    SHAPE ABUTMENT ;
    PORT
      LAYER M4 ;
      RECT 0.000 66.288 0.024 66.312 ;
    END
  END wd_in[94]
  PIN wd_in[95]
    DIRECTION INPUT ;
    USE SIGNAL ;
    SHAPE ABUTMENT ;
    PORT
      LAYER M4 ;
      RECT 0.000 66.576 0.024 66.600 ;
    END
  END wd_in[95]
  PIN wd_in[96]
    DIRECTION INPUT ;
    USE SIGNAL ;
    SHAPE ABUTMENT ;
    PORT
      LAYER M4 ;
      RECT 0.000 66.864 0.024 66.888 ;
    END
  END wd_in[96]
  PIN wd_in[97]
    DIRECTION INPUT ;
    USE SIGNAL ;
    SHAPE ABUTMENT ;
    PORT
      LAYER M4 ;
      RECT 0.000 67.152 0.024 67.176 ;
    END
  END wd_in[97]
  PIN wd_in[98]
    DIRECTION INPUT ;
    USE SIGNAL ;
    SHAPE ABUTMENT ;
    PORT
      LAYER M4 ;
      RECT 0.000 67.440 0.024 67.464 ;
    END
  END wd_in[98]
  PIN wd_in[99]
    DIRECTION INPUT ;
    USE SIGNAL ;
    SHAPE ABUTMENT ;
    PORT
      LAYER M4 ;
      RECT 0.000 67.728 0.024 67.752 ;
    END
  END wd_in[99]
  PIN wd_in[100]
    DIRECTION INPUT ;
    USE SIGNAL ;
    SHAPE ABUTMENT ;
    PORT
      LAYER M4 ;
      RECT 0.000 68.016 0.024 68.040 ;
    END
  END wd_in[100]
  PIN wd_in[101]
    DIRECTION INPUT ;
    USE SIGNAL ;
    SHAPE ABUTMENT ;
    PORT
      LAYER M4 ;
      RECT 0.000 68.304 0.024 68.328 ;
    END
  END wd_in[101]
  PIN wd_in[102]
    DIRECTION INPUT ;
    USE SIGNAL ;
    SHAPE ABUTMENT ;
    PORT
      LAYER M4 ;
      RECT 0.000 68.592 0.024 68.616 ;
    END
  END wd_in[102]
  PIN wd_in[103]
    DIRECTION INPUT ;
    USE SIGNAL ;
    SHAPE ABUTMENT ;
    PORT
      LAYER M4 ;
      RECT 0.000 68.880 0.024 68.904 ;
    END
  END wd_in[103]
  PIN wd_in[104]
    DIRECTION INPUT ;
    USE SIGNAL ;
    SHAPE ABUTMENT ;
    PORT
      LAYER M4 ;
      RECT 0.000 69.168 0.024 69.192 ;
    END
  END wd_in[104]
  PIN wd_in[105]
    DIRECTION INPUT ;
    USE SIGNAL ;
    SHAPE ABUTMENT ;
    PORT
      LAYER M4 ;
      RECT 0.000 69.456 0.024 69.480 ;
    END
  END wd_in[105]
  PIN wd_in[106]
    DIRECTION INPUT ;
    USE SIGNAL ;
    SHAPE ABUTMENT ;
    PORT
      LAYER M4 ;
      RECT 0.000 69.744 0.024 69.768 ;
    END
  END wd_in[106]
  PIN wd_in[107]
    DIRECTION INPUT ;
    USE SIGNAL ;
    SHAPE ABUTMENT ;
    PORT
      LAYER M4 ;
      RECT 0.000 70.032 0.024 70.056 ;
    END
  END wd_in[107]
  PIN wd_in[108]
    DIRECTION INPUT ;
    USE SIGNAL ;
    SHAPE ABUTMENT ;
    PORT
      LAYER M4 ;
      RECT 0.000 70.320 0.024 70.344 ;
    END
  END wd_in[108]
  PIN wd_in[109]
    DIRECTION INPUT ;
    USE SIGNAL ;
    SHAPE ABUTMENT ;
    PORT
      LAYER M4 ;
      RECT 0.000 70.608 0.024 70.632 ;
    END
  END wd_in[109]
  PIN wd_in[110]
    DIRECTION INPUT ;
    USE SIGNAL ;
    SHAPE ABUTMENT ;
    PORT
      LAYER M4 ;
      RECT 0.000 70.896 0.024 70.920 ;
    END
  END wd_in[110]
  PIN wd_in[111]
    DIRECTION INPUT ;
    USE SIGNAL ;
    SHAPE ABUTMENT ;
    PORT
      LAYER M4 ;
      RECT 0.000 71.184 0.024 71.208 ;
    END
  END wd_in[111]
  PIN wd_in[112]
    DIRECTION INPUT ;
    USE SIGNAL ;
    SHAPE ABUTMENT ;
    PORT
      LAYER M4 ;
      RECT 0.000 71.472 0.024 71.496 ;
    END
  END wd_in[112]
  PIN wd_in[113]
    DIRECTION INPUT ;
    USE SIGNAL ;
    SHAPE ABUTMENT ;
    PORT
      LAYER M4 ;
      RECT 0.000 71.760 0.024 71.784 ;
    END
  END wd_in[113]
  PIN wd_in[114]
    DIRECTION INPUT ;
    USE SIGNAL ;
    SHAPE ABUTMENT ;
    PORT
      LAYER M4 ;
      RECT 0.000 72.048 0.024 72.072 ;
    END
  END wd_in[114]
  PIN wd_in[115]
    DIRECTION INPUT ;
    USE SIGNAL ;
    SHAPE ABUTMENT ;
    PORT
      LAYER M4 ;
      RECT 0.000 72.336 0.024 72.360 ;
    END
  END wd_in[115]
  PIN wd_in[116]
    DIRECTION INPUT ;
    USE SIGNAL ;
    SHAPE ABUTMENT ;
    PORT
      LAYER M4 ;
      RECT 0.000 72.624 0.024 72.648 ;
    END
  END wd_in[116]
  PIN wd_in[117]
    DIRECTION INPUT ;
    USE SIGNAL ;
    SHAPE ABUTMENT ;
    PORT
      LAYER M4 ;
      RECT 0.000 72.912 0.024 72.936 ;
    END
  END wd_in[117]
  PIN wd_in[118]
    DIRECTION INPUT ;
    USE SIGNAL ;
    SHAPE ABUTMENT ;
    PORT
      LAYER M4 ;
      RECT 0.000 73.200 0.024 73.224 ;
    END
  END wd_in[118]
  PIN wd_in[119]
    DIRECTION INPUT ;
    USE SIGNAL ;
    SHAPE ABUTMENT ;
    PORT
      LAYER M4 ;
      RECT 0.000 73.488 0.024 73.512 ;
    END
  END wd_in[119]
  PIN wd_in[120]
    DIRECTION INPUT ;
    USE SIGNAL ;
    SHAPE ABUTMENT ;
    PORT
      LAYER M4 ;
      RECT 0.000 73.776 0.024 73.800 ;
    END
  END wd_in[120]
  PIN wd_in[121]
    DIRECTION INPUT ;
    USE SIGNAL ;
    SHAPE ABUTMENT ;
    PORT
      LAYER M4 ;
      RECT 0.000 74.064 0.024 74.088 ;
    END
  END wd_in[121]
  PIN wd_in[122]
    DIRECTION INPUT ;
    USE SIGNAL ;
    SHAPE ABUTMENT ;
    PORT
      LAYER M4 ;
      RECT 0.000 74.352 0.024 74.376 ;
    END
  END wd_in[122]
  PIN wd_in[123]
    DIRECTION INPUT ;
    USE SIGNAL ;
    SHAPE ABUTMENT ;
    PORT
      LAYER M4 ;
      RECT 0.000 74.640 0.024 74.664 ;
    END
  END wd_in[123]
  PIN wd_in[124]
    DIRECTION INPUT ;
    USE SIGNAL ;
    SHAPE ABUTMENT ;
    PORT
      LAYER M4 ;
      RECT 0.000 74.928 0.024 74.952 ;
    END
  END wd_in[124]
  PIN wd_in[125]
    DIRECTION INPUT ;
    USE SIGNAL ;
    SHAPE ABUTMENT ;
    PORT
      LAYER M4 ;
      RECT 0.000 75.216 0.024 75.240 ;
    END
  END wd_in[125]
  PIN wd_in[126]
    DIRECTION INPUT ;
    USE SIGNAL ;
    SHAPE ABUTMENT ;
    PORT
      LAYER M4 ;
      RECT 0.000 75.504 0.024 75.528 ;
    END
  END wd_in[126]
  PIN wd_in[127]
    DIRECTION INPUT ;
    USE SIGNAL ;
    SHAPE ABUTMENT ;
    PORT
      LAYER M4 ;
      RECT 0.000 75.792 0.024 75.816 ;
    END
  END wd_in[127]
  PIN addr_in[0]
    DIRECTION INPUT ;
    USE SIGNAL ;
    SHAPE ABUTMENT ;
    PORT
      LAYER M4 ;
      RECT 0.000 78.384 0.024 78.408 ;
    END
  END addr_in[0]
  PIN addr_in[1]
    DIRECTION INPUT ;
    USE SIGNAL ;
    SHAPE ABUTMENT ;
    PORT
      LAYER M4 ;
      RECT 0.000 78.672 0.024 78.696 ;
    END
  END addr_in[1]
  PIN addr_in[2]
    DIRECTION INPUT ;
    USE SIGNAL ;
    SHAPE ABUTMENT ;
    PORT
      LAYER M4 ;
      RECT 0.000 78.960 0.024 78.984 ;
    END
  END addr_in[2]
  PIN addr_in[3]
    DIRECTION INPUT ;
    USE SIGNAL ;
    SHAPE ABUTMENT ;
    PORT
      LAYER M4 ;
      RECT 0.000 79.248 0.024 79.272 ;
    END
  END addr_in[3]
  PIN addr_in[4]
    DIRECTION INPUT ;
    USE SIGNAL ;
    SHAPE ABUTMENT ;
    PORT
      LAYER M4 ;
      RECT 0.000 79.536 0.024 79.560 ;
    END
  END addr_in[4]
  PIN addr_in[5]
    DIRECTION INPUT ;
    USE SIGNAL ;
    SHAPE ABUTMENT ;
    PORT
      LAYER M4 ;
      RECT 0.000 79.824 0.024 79.848 ;
    END
  END addr_in[5]
  PIN addr_in[6]
    DIRECTION INPUT ;
    USE SIGNAL ;
    SHAPE ABUTMENT ;
    PORT
      LAYER M4 ;
      RECT 0.000 80.112 0.024 80.136 ;
    END
  END addr_in[6]
  PIN addr_in[7]
    DIRECTION INPUT ;
    USE SIGNAL ;
    SHAPE ABUTMENT ;
    PORT
      LAYER M4 ;
      RECT 0.000 80.400 0.024 80.424 ;
    END
  END addr_in[7]
  PIN we_in
    DIRECTION INPUT ;
    USE SIGNAL ;
    SHAPE ABUTMENT ;
    PORT
      LAYER M4 ;
      RECT 0.000 82.992 0.024 83.016 ;
    END
  END we_in
  PIN ce_in
    DIRECTION INPUT ;
    USE SIGNAL ;
    SHAPE ABUTMENT ;
    PORT
      LAYER M4 ;
      RECT 0.000 83.280 0.024 83.304 ;
    END
  END ce_in
  PIN clk
    DIRECTION INPUT ;
    USE SIGNAL ;
    SHAPE ABUTMENT ;
    PORT
      LAYER M4 ;
      RECT 0.000 83.568 0.024 83.592 ;
    END
  END clk
  PIN VSS
    DIRECTION INOUT ;
    USE GROUND ;
    PORT
      LAYER M4 ;
      RECT 0.048 0.000 16.672 0.096 ;
      RECT 0.048 0.768 16.672 0.864 ;
      RECT 0.048 1.536 16.672 1.632 ;
      RECT 0.048 2.304 16.672 2.400 ;
      RECT 0.048 3.072 16.672 3.168 ;
      RECT 0.048 3.840 16.672 3.936 ;
      RECT 0.048 4.608 16.672 4.704 ;
      RECT 0.048 5.376 16.672 5.472 ;
      RECT 0.048 6.144 16.672 6.240 ;
      RECT 0.048 6.912 16.672 7.008 ;
      RECT 0.048 7.680 16.672 7.776 ;
      RECT 0.048 8.448 16.672 8.544 ;
      RECT 0.048 9.216 16.672 9.312 ;
      RECT 0.048 9.984 16.672 10.080 ;
      RECT 0.048 10.752 16.672 10.848 ;
      RECT 0.048 11.520 16.672 11.616 ;
      RECT 0.048 12.288 16.672 12.384 ;
      RECT 0.048 13.056 16.672 13.152 ;
      RECT 0.048 13.824 16.672 13.920 ;
      RECT 0.048 14.592 16.672 14.688 ;
      RECT 0.048 15.360 16.672 15.456 ;
      RECT 0.048 16.128 16.672 16.224 ;
      RECT 0.048 16.896 16.672 16.992 ;
      RECT 0.048 17.664 16.672 17.760 ;
      RECT 0.048 18.432 16.672 18.528 ;
      RECT 0.048 19.200 16.672 19.296 ;
      RECT 0.048 19.968 16.672 20.064 ;
      RECT 0.048 20.736 16.672 20.832 ;
      RECT 0.048 21.504 16.672 21.600 ;
      RECT 0.048 22.272 16.672 22.368 ;
      RECT 0.048 23.040 16.672 23.136 ;
      RECT 0.048 23.808 16.672 23.904 ;
      RECT 0.048 24.576 16.672 24.672 ;
      RECT 0.048 25.344 16.672 25.440 ;
      RECT 0.048 26.112 16.672 26.208 ;
      RECT 0.048 26.880 16.672 26.976 ;
      RECT 0.048 27.648 16.672 27.744 ;
      RECT 0.048 28.416 16.672 28.512 ;
      RECT 0.048 29.184 16.672 29.280 ;
      RECT 0.048 29.952 16.672 30.048 ;
      RECT 0.048 30.720 16.672 30.816 ;
      RECT 0.048 31.488 16.672 31.584 ;
      RECT 0.048 32.256 16.672 32.352 ;
      RECT 0.048 33.024 16.672 33.120 ;
      RECT 0.048 33.792 16.672 33.888 ;
      RECT 0.048 34.560 16.672 34.656 ;
      RECT 0.048 35.328 16.672 35.424 ;
      RECT 0.048 36.096 16.672 36.192 ;
      RECT 0.048 36.864 16.672 36.960 ;
      RECT 0.048 37.632 16.672 37.728 ;
      RECT 0.048 38.400 16.672 38.496 ;
      RECT 0.048 39.168 16.672 39.264 ;
      RECT 0.048 39.936 16.672 40.032 ;
      RECT 0.048 40.704 16.672 40.800 ;
      RECT 0.048 41.472 16.672 41.568 ;
      RECT 0.048 42.240 16.672 42.336 ;
      RECT 0.048 43.008 16.672 43.104 ;
      RECT 0.048 43.776 16.672 43.872 ;
      RECT 0.048 44.544 16.672 44.640 ;
      RECT 0.048 45.312 16.672 45.408 ;
      RECT 0.048 46.080 16.672 46.176 ;
      RECT 0.048 46.848 16.672 46.944 ;
      RECT 0.048 47.616 16.672 47.712 ;
      RECT 0.048 48.384 16.672 48.480 ;
      RECT 0.048 49.152 16.672 49.248 ;
      RECT 0.048 49.920 16.672 50.016 ;
      RECT 0.048 50.688 16.672 50.784 ;
      RECT 0.048 51.456 16.672 51.552 ;
      RECT 0.048 52.224 16.672 52.320 ;
      RECT 0.048 52.992 16.672 53.088 ;
      RECT 0.048 53.760 16.672 53.856 ;
      RECT 0.048 54.528 16.672 54.624 ;
      RECT 0.048 55.296 16.672 55.392 ;
      RECT 0.048 56.064 16.672 56.160 ;
      RECT 0.048 56.832 16.672 56.928 ;
      RECT 0.048 57.600 16.672 57.696 ;
      RECT 0.048 58.368 16.672 58.464 ;
      RECT 0.048 59.136 16.672 59.232 ;
      RECT 0.048 59.904 16.672 60.000 ;
      RECT 0.048 60.672 16.672 60.768 ;
      RECT 0.048 61.440 16.672 61.536 ;
      RECT 0.048 62.208 16.672 62.304 ;
      RECT 0.048 62.976 16.672 63.072 ;
      RECT 0.048 63.744 16.672 63.840 ;
      RECT 0.048 64.512 16.672 64.608 ;
      RECT 0.048 65.280 16.672 65.376 ;
      RECT 0.048 66.048 16.672 66.144 ;
      RECT 0.048 66.816 16.672 66.912 ;
      RECT 0.048 67.584 16.672 67.680 ;
      RECT 0.048 68.352 16.672 68.448 ;
      RECT 0.048 69.120 16.672 69.216 ;
      RECT 0.048 69.888 16.672 69.984 ;
      RECT 0.048 70.656 16.672 70.752 ;
      RECT 0.048 71.424 16.672 71.520 ;
      RECT 0.048 72.192 16.672 72.288 ;
      RECT 0.048 72.960 16.672 73.056 ;
      RECT 0.048 73.728 16.672 73.824 ;
      RECT 0.048 74.496 16.672 74.592 ;
      RECT 0.048 75.264 16.672 75.360 ;
      RECT 0.048 76.032 16.672 76.128 ;
      RECT 0.048 76.800 16.672 76.896 ;
      RECT 0.048 77.568 16.672 77.664 ;
      RECT 0.048 78.336 16.672 78.432 ;
      RECT 0.048 79.104 16.672 79.200 ;
      RECT 0.048 79.872 16.672 79.968 ;
      RECT 0.048 80.640 16.672 80.736 ;
      RECT 0.048 81.408 16.672 81.504 ;
      RECT 0.048 82.176 16.672 82.272 ;
      RECT 0.048 82.944 16.672 83.040 ;
      RECT 0.048 83.712 16.672 83.808 ;
    END
  END VSS
  PIN VDD
    DIRECTION INOUT ;
    USE POWER ;
    PORT
      LAYER M4 ;
      RECT 0.048 0.384 16.672 0.480 ;
      RECT 0.048 1.152 16.672 1.248 ;
      RECT 0.048 1.920 16.672 2.016 ;
      RECT 0.048 2.688 16.672 2.784 ;
      RECT 0.048 3.456 16.672 3.552 ;
      RECT 0.048 4.224 16.672 4.320 ;
      RECT 0.048 4.992 16.672 5.088 ;
      RECT 0.048 5.760 16.672 5.856 ;
      RECT 0.048 6.528 16.672 6.624 ;
      RECT 0.048 7.296 16.672 7.392 ;
      RECT 0.048 8.064 16.672 8.160 ;
      RECT 0.048 8.832 16.672 8.928 ;
      RECT 0.048 9.600 16.672 9.696 ;
      RECT 0.048 10.368 16.672 10.464 ;
      RECT 0.048 11.136 16.672 11.232 ;
      RECT 0.048 11.904 16.672 12.000 ;
      RECT 0.048 12.672 16.672 12.768 ;
      RECT 0.048 13.440 16.672 13.536 ;
      RECT 0.048 14.208 16.672 14.304 ;
      RECT 0.048 14.976 16.672 15.072 ;
      RECT 0.048 15.744 16.672 15.840 ;
      RECT 0.048 16.512 16.672 16.608 ;
      RECT 0.048 17.280 16.672 17.376 ;
      RECT 0.048 18.048 16.672 18.144 ;
      RECT 0.048 18.816 16.672 18.912 ;
      RECT 0.048 19.584 16.672 19.680 ;
      RECT 0.048 20.352 16.672 20.448 ;
      RECT 0.048 21.120 16.672 21.216 ;
      RECT 0.048 21.888 16.672 21.984 ;
      RECT 0.048 22.656 16.672 22.752 ;
      RECT 0.048 23.424 16.672 23.520 ;
      RECT 0.048 24.192 16.672 24.288 ;
      RECT 0.048 24.960 16.672 25.056 ;
      RECT 0.048 25.728 16.672 25.824 ;
      RECT 0.048 26.496 16.672 26.592 ;
      RECT 0.048 27.264 16.672 27.360 ;
      RECT 0.048 28.032 16.672 28.128 ;
      RECT 0.048 28.800 16.672 28.896 ;
      RECT 0.048 29.568 16.672 29.664 ;
      RECT 0.048 30.336 16.672 30.432 ;
      RECT 0.048 31.104 16.672 31.200 ;
      RECT 0.048 31.872 16.672 31.968 ;
      RECT 0.048 32.640 16.672 32.736 ;
      RECT 0.048 33.408 16.672 33.504 ;
      RECT 0.048 34.176 16.672 34.272 ;
      RECT 0.048 34.944 16.672 35.040 ;
      RECT 0.048 35.712 16.672 35.808 ;
      RECT 0.048 36.480 16.672 36.576 ;
      RECT 0.048 37.248 16.672 37.344 ;
      RECT 0.048 38.016 16.672 38.112 ;
      RECT 0.048 38.784 16.672 38.880 ;
      RECT 0.048 39.552 16.672 39.648 ;
      RECT 0.048 40.320 16.672 40.416 ;
      RECT 0.048 41.088 16.672 41.184 ;
      RECT 0.048 41.856 16.672 41.952 ;
      RECT 0.048 42.624 16.672 42.720 ;
      RECT 0.048 43.392 16.672 43.488 ;
      RECT 0.048 44.160 16.672 44.256 ;
      RECT 0.048 44.928 16.672 45.024 ;
      RECT 0.048 45.696 16.672 45.792 ;
      RECT 0.048 46.464 16.672 46.560 ;
      RECT 0.048 47.232 16.672 47.328 ;
      RECT 0.048 48.000 16.672 48.096 ;
      RECT 0.048 48.768 16.672 48.864 ;
      RECT 0.048 49.536 16.672 49.632 ;
      RECT 0.048 50.304 16.672 50.400 ;
      RECT 0.048 51.072 16.672 51.168 ;
      RECT 0.048 51.840 16.672 51.936 ;
      RECT 0.048 52.608 16.672 52.704 ;
      RECT 0.048 53.376 16.672 53.472 ;
      RECT 0.048 54.144 16.672 54.240 ;
      RECT 0.048 54.912 16.672 55.008 ;
      RECT 0.048 55.680 16.672 55.776 ;
      RECT 0.048 56.448 16.672 56.544 ;
      RECT 0.048 57.216 16.672 57.312 ;
      RECT 0.048 57.984 16.672 58.080 ;
      RECT 0.048 58.752 16.672 58.848 ;
      RECT 0.048 59.520 16.672 59.616 ;
      RECT 0.048 60.288 16.672 60.384 ;
      RECT 0.048 61.056 16.672 61.152 ;
      RECT 0.048 61.824 16.672 61.920 ;
      RECT 0.048 62.592 16.672 62.688 ;
      RECT 0.048 63.360 16.672 63.456 ;
      RECT 0.048 64.128 16.672 64.224 ;
      RECT 0.048 64.896 16.672 64.992 ;
      RECT 0.048 65.664 16.672 65.760 ;
      RECT 0.048 66.432 16.672 66.528 ;
      RECT 0.048 67.200 16.672 67.296 ;
      RECT 0.048 67.968 16.672 68.064 ;
      RECT 0.048 68.736 16.672 68.832 ;
      RECT 0.048 69.504 16.672 69.600 ;
      RECT 0.048 70.272 16.672 70.368 ;
      RECT 0.048 71.040 16.672 71.136 ;
      RECT 0.048 71.808 16.672 71.904 ;
      RECT 0.048 72.576 16.672 72.672 ;
      RECT 0.048 73.344 16.672 73.440 ;
      RECT 0.048 74.112 16.672 74.208 ;
      RECT 0.048 74.880 16.672 74.976 ;
      RECT 0.048 75.648 16.672 75.744 ;
      RECT 0.048 76.416 16.672 76.512 ;
      RECT 0.048 77.184 16.672 77.280 ;
      RECT 0.048 77.952 16.672 78.048 ;
      RECT 0.048 78.720 16.672 78.816 ;
      RECT 0.048 79.488 16.672 79.584 ;
      RECT 0.048 80.256 16.672 80.352 ;
      RECT 0.048 81.024 16.672 81.120 ;
      RECT 0.048 81.792 16.672 81.888 ;
      RECT 0.048 82.560 16.672 82.656 ;
      RECT 0.048 83.328 16.672 83.424 ;
    END
  END VDD
  OBS
    LAYER M1 ;
    RECT 0 0 16.720 84.000 ;
    LAYER M2 ;
    RECT 0 0 16.720 84.000 ;
    LAYER M3 ;
    RECT 0 0 16.720 84.000 ;
    LAYER M4 ;
    RECT 0 0 16.720 84.000 ;
  END
END fakeram_256x128

END LIBRARY
